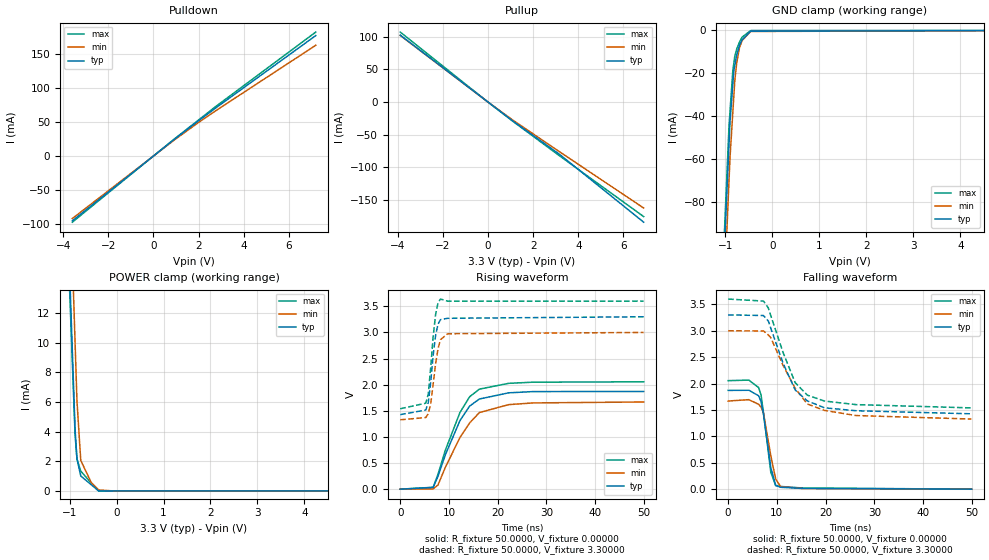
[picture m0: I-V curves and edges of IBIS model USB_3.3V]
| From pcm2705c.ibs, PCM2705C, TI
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[Model] USB_3.3V
Model_type I/O
Vinl  = 0.8V
Vinh  = 2.0V
Vref  = 0.90000V
Rref  = 50.0000ohms
Cref  = 2.00000pF
Vmeas = 1.6500V
C_comp  3.228pF   3.041pF   4.839pF
[Model Spec]
Vmeas  1.6500V  1.5000V   1.8000V
| variable   typ   min   max
[Voltage Range]   3.30000V  3.00000V  3.60000V
[POWER Clamp Reference]  3.30000V  3.00000V  3.60000V
[Pullup Reference]   3.30000V  3.00000V  3.60000V
[Pulldown Reference]   0.00000V  0.00000V  0.00000V
[GND Clamp Reference]   0.00000V  0.00000V  0.00000V
[Temperature Range]   25   85   -25
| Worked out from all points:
|   slope of the pulldown table from 0 to 0.495 V, typ, clamps not added: 37.6 ohm
|   slope of the pullup table from 0 to 0.495 V, typ, clamps not added: 37.9 ohm
|   GND clamp passes 1 mA (typ) near -0.51 V on its own axis
|   POWER clamp passes 1 mA (typ) near -0.76 V on its own axis
|   rising waveform, R_fixture 50.0000, V_fixture 0.00000: 20-80 % time 5.29ns typ, 5.99ns min, 5.27ns max; typ from 0 V to 1.87 V
|   falling waveform, R_fixture 50.0000, V_fixture 0.00000: 20-80 % time 1.74ns typ, 1.91ns min, 1.65ns max; typ from 1.87 V to 0 V
|   falling waveform, R_fixture 50.0000, V_fixture 3.30000: 20-80 % time 5.26ns typ, 5.92ns min, 5.07ns max; typ from 3.3 V to 1.43 V
|   rising waveform, R_fixture 50.0000, V_fixture 3.30000: 20-80 % time 1.3ns typ, 1.42ns min, 1.19ns max; typ from 1.43 V to 3.3 V
[GND Clamp]
-3.6V     -1.373A    -1.433A    -1.4A
-3V       -1.077A    -1.128A    -1.096A
-921.4mV  -52.4mA    -69.4mA    -43.98mA
-901.1mV  -42.44mA   -59.11mA   -37.62mA
-840.7mV  -24.8mA    -37.91mA   -18.61mA
-820.5mV  -18.92mA   -30.84mA   -15.41mA
-800.2mV  -16.45mA   -23.7mA    -12.17mA
-759.8mV  -11.56mA   -15.32mA   -8.783mA
-699.3mV  -7.003mA   -8.096mA   -5.441mA
-643.5mV  -4.394mA   -4.721mA   -3.162mA
-461.5mV  -406.7uA   -526.5uA   -106.5uA
7.2V      0A         0A         0A
[Pulldown]
-3.6V     -95.71mA   -92.3mA    -97.72mA
921.3mV   24.5mA     23.58mA    25mA
1.963V    51.14mA    48.71mA    52.21mA
2.741V    70.45mA    66.39mA    72.56mA
7.2V      177.8mA    163.5mA    183mA
[Pullup]
-3.9V     102.7mA    102.2mA    107.4mA
0V        -130.5uA   -178.6uA   -213.4uA
1.099V    -29.12mA   -27.79mA   -29.6mA
3.178V    -80.55mA   -76.57mA   -82.79mA
6.9V      -184.4mA   -162.6mA   -175.8mA
[POWER Clamp]
-3.9V     278.4mA    305.6mA    270.4mA
-1.079V   22.05mA    29.31mA    20.34mA
-882.6mV  4.164mA    10.04mA    3.782mA
-841.9mV  2.164mA    6.05mA     2.149mA
-761.4mV  1.009mA    2.059mA    1.334mA
-538.5mV  418.3uA    564uA      534.2uA
-380.7mV  0A         62.88uA    0A
-60.9mV   0A         0A         0A
6.9V      0A         0A         0A
[Rising Waveform]
R_fixture = 50.0000
V_fixture = 0.00000
V_fixture_min = 0.00000
V_fixture_max = 0.00000
0s        0V         0V         0V
6.75ns    33.04mV    5.052mV    36.02mV
7.75ns    246.2mV    79.88mV    285.5mV
9.25ns    656.1mV    416.7mV    744.1mV
12.25ns   1.312V     988.6mV    1.467V
14.25ns   1.591V     1.269V     1.77V
16.25ns   1.726V     1.467V     1.915V
22.25ns   1.844V     1.618V     2.026V
27.25ns   1.868V     1.651V     2.048V
49.95ns   1.87V      1.669V     2.055V
[Falling Waveform]
R_fixture = 50.0000
V_fixture = 0.00000
V_fixture_min = 0.00000
V_fixture_max = 0.00000
0s        1.87V      1.669V     2.055V
4.25ns    1.873V     1.695V     2.065V
6.25ns    1.769V     1.607V     1.924V
6.75ns    1.658V     1.554V     1.783V
7.25ns    1.415V     1.441V     1.451V
8.75ns    408.3mV    632.3mV    320.8mV
9.75ns    73.75mV    193.2mV    66.52mV
10.75ns   35.96mV    48.47mV    51.52mV
15.25ns   14.94mV    11.23mV    22.49mV
49.95ns   0V         0V         0V
[Falling Waveform]
R_fixture = 50.0000
V_fixture = 3.30000
V_fixture_min = 3.00000
V_fixture_max = 3.60000
0s        3.3V       3V         3.6V
7.25ns    3.288V     2.996V     3.562V
8.25ns    3.184V     2.92V      3.43V
8.75ns    3.047V     2.868V     3.284V
11.25ns   2.39V      2.347V     2.593V
13.75ns   1.879V     1.909V     2.017V
16.25ns   1.672V     1.613V     1.78V
19.75ns   1.541V     1.491V     1.669V
26.25ns   1.485V     1.394V     1.601V
49.95ns   1.427V     1.328V     1.539V
[Rising Waveform]
R_fixture = 50.0000
V_fixture = 3.30000
V_fixture_min = 3.00000
V_fixture_max = 3.60000
0s        1.427V     1.328V     1.539V
5.25ns    1.515V     1.371V     1.646V
5.75ns    1.655V     1.447V     1.819V
6.25ns    2.048V     1.628V     2.327V
6.75ns    2.558V     2.006V     2.917V
7.25ns    2.938V     2.397V     3.339V
7.75ns    3.159V     2.686V     3.567V
8.25ns    3.245V     2.863V     3.639V
9.75ns    3.271V     2.975V     3.599V
49.95ns   3.3V       3V         3.6V
[Ramp]
| variable typ   min   max
dV/dt_r   1.12124/5.28805n  1.00056/5.98045n  1.23190/5.98290n
dV/dt_f   1.12606/5.23878n  1.00481/5.90076n  1.23820/5.03044n
R_load  =  50.0000Ohms
